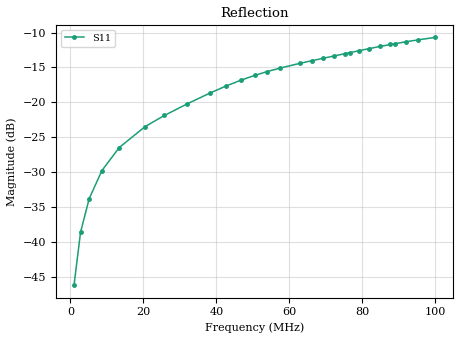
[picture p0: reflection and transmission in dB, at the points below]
# MHz S RI R 50.0
! SimSmith 18.4g
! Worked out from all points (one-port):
!   1000 points, 1 MHz to 100 MHz, reference 50 ohm
!   lowest |S11| = -46.1 dB at 1 MHz (marker M1), VSWR 1.01, Z = 50.2 + j0.447 ohm
!   |S11| at or under -10 dB: start of sweep to end of sweep
!   S11 on the Smith chart (normalised r, x): 1 MHz: 1.00, +0.01; 42.62 MHz: 1.12, +0.25; 76.51 MHz: 0.80, +0.37; 89 MHz: 1.70, -0.14; 100 MHz: 0.72, -0.43
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1  0.00213 0.00445
2.783784  0.00677 0.00968
5.162162  0.0163 0.0125
8.630631  0.0321 0.00526
13.38739  0.0406 -0.0248
20.42342  -0.00536 -0.0668
25.77478  -0.0657 -0.0469
32.01802  -0.0895 0.0391
38.16216  -0.0173 0.1151
42.62162  0.0709 0.11
46.88288  0.1375 0.0451
50.54955  0.1507 -0.041
53.81982  0.1174 -0.1172
57.38739  0.0382 -0.1717
62.93694  -0.1181 -0.1494
66.30631  -0.1864 -0.0702
69.27928  -0.2054 0.0247
72.15315  -0.1791 0.1183
75.32432  -0.1022 0.1988
76.51351  -0.0634 0.2179
79.18919  0.0345 0.2321
81.76577  0.1289 0.2051
84.93694  0.2206 0.1211
87.71171  0.2592 0.0153
89  0.2605 -0.0384
91.97297  0.2209 -0.1578
95.14414  0.1205 -0.2526
100  -0.0947 -0.2761
